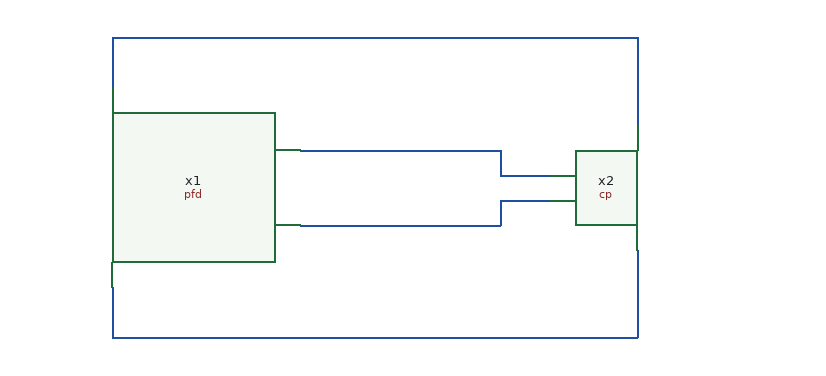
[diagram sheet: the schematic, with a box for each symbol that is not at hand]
v {xschem version=3.4.5 file_version=1.2
}
G {}
K {}
V {}
S {}
E {}
N 11400 -10620 11400 -10580 {}
N 11400 -10620 11820 -10620 {}
N 11820 -10620 11820 -10550 {}
N 11400 -10420 11400 -10380 {}
N 11400 -10380 11820 -10380 {}
N 11820 -10450 11820 -10380 {}
N 11550 -10530 11710 -10530 {}
N 11710 -10510 11750 -10510 {}
N 11710 -10530 11710 -10510 {}
N 11710 -10490 11750 -10490 {}
N 11550 -10470 11710 -10470 {}
N 11710 -10490 11710 -10470 {}
C {pfd/pfd.sym} 11400 -10500 0 0 {name=x1}
C {cp/cp.sym} 11820 -10500 0 0 {name=x2}
